One B-rep face of a CAD part: STEP entity #398.
In plain terms, the planar face has unit normal (0, 0, 1).
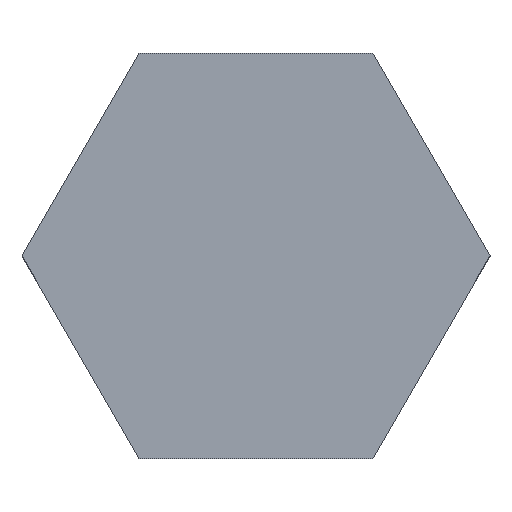
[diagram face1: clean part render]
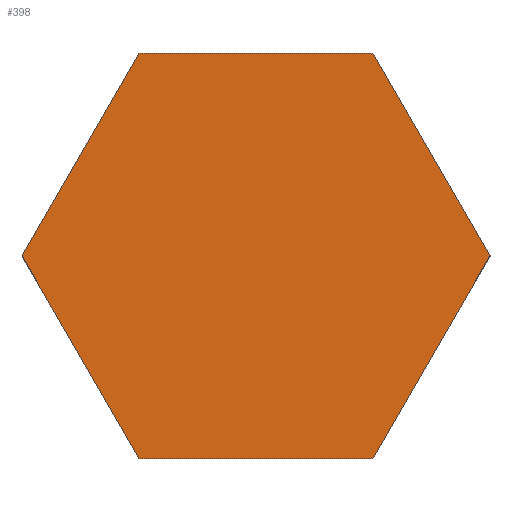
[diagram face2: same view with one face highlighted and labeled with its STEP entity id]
Its self-contained STEP definition (entity closure, numbers rounded to 3 decimals):
#24 = VERTEX_POINT('',#25);
#25 = CARTESIAN_POINT('',(15.,0.,60.));
#32 = PLANE('',#33);
#33 = AXIS2_PLACEMENT_3D('',#34,#35,#36);
#34 = CARTESIAN_POINT('',(15.,0.,54.));
#35 = DIRECTION('',(-0.866,-0.5,0.));
#36 = DIRECTION('',(-0.5,0.866,0.));
#44 = PLANE('',#45);
#45 = AXIS2_PLACEMENT_3D('',#46,#47,#48);
#46 = CARTESIAN_POINT('',(7.5,-12.99,54.));
#47 = DIRECTION('',(-0.866,0.5,0.));
#48 = DIRECTION('',(0.5,0.866,0.));
#56 = EDGE_CURVE('',#24,#57,#59,.T.);
#57 = VERTEX_POINT('',#58);
#58 = CARTESIAN_POINT('',(7.5,12.99,60.));
#59 = SURFACE_CURVE('',#60,(#64,#71),.PCURVE_S1.);
#60 = LINE('',#61,#62);
#61 = CARTESIAN_POINT('',(15.,0.,60.));
#62 = VECTOR('',#63,1.);
#63 = DIRECTION('',(-0.5,0.866,0.));
#64 = PCURVE('',#32,#65);
#65 = DEFINITIONAL_REPRESENTATION('',(#66),#70);
#66 = LINE('',#67,#68);
#67 = CARTESIAN_POINT('',(0.,-6.));
#68 = VECTOR('',#69,1.);
#69 = DIRECTION('',(1.,0.));
#70 = ( GEOMETRIC_REPRESENTATION_CONTEXT(2) 
PARAMETRIC_REPRESENTATION_CONTEXT() REPRESENTATION_CONTEXT('2D SPACE',''
  ) );
#71 = PCURVE('',#72,#77);
#72 = PLANE('',#73);
#73 = AXIS2_PLACEMENT_3D('',#74,#75,#76);
#74 = CARTESIAN_POINT('',(0.,0.,60.));
#75 = DIRECTION('',(0.,0.,1.));
#76 = DIRECTION('',(1.,0.,-0.));
#77 = DEFINITIONAL_REPRESENTATION('',(#78),#82);
#78 = LINE('',#79,#80);
#79 = CARTESIAN_POINT('',(15.,0.));
#80 = VECTOR('',#81,1.);
#81 = DIRECTION('',(-0.5,0.866));
#82 = ( GEOMETRIC_REPRESENTATION_CONTEXT(2) 
PARAMETRIC_REPRESENTATION_CONTEXT() REPRESENTATION_CONTEXT('2D SPACE',''
  ) );
#100 = PLANE('',#101);
#101 = AXIS2_PLACEMENT_3D('',#102,#103,#104);
#102 = CARTESIAN_POINT('',(7.5,12.99,54.));
#103 = DIRECTION('',(0.,-1.,0.));
#104 = DIRECTION('',(-1.,0.,0.));
#144 = VERTEX_POINT('',#145);
#145 = CARTESIAN_POINT('',(7.5,-12.99,60.));
#159 = PLANE('',#160);
#160 = AXIS2_PLACEMENT_3D('',#161,#162,#163);
#161 = CARTESIAN_POINT('',(-7.5,-12.99,54.));
#162 = DIRECTION('',(0.,1.,-0.));
#163 = DIRECTION('',(1.,0.,0.));
#171 = EDGE_CURVE('',#144,#24,#172,.T.);
#172 = SURFACE_CURVE('',#173,(#177,#184),.PCURVE_S1.);
#173 = LINE('',#174,#175);
#174 = CARTESIAN_POINT('',(7.5,-12.99,60.));
#175 = VECTOR('',#176,1.);
#176 = DIRECTION('',(0.5,0.866,0.));
#177 = PCURVE('',#44,#178);
#178 = DEFINITIONAL_REPRESENTATION('',(#179),#183);
#179 = LINE('',#180,#181);
#180 = CARTESIAN_POINT('',(0.,-6.));
#181 = VECTOR('',#182,1.);
#182 = DIRECTION('',(1.,0.));
#183 = ( GEOMETRIC_REPRESENTATION_CONTEXT(2) 
PARAMETRIC_REPRESENTATION_CONTEXT() REPRESENTATION_CONTEXT('2D SPACE',''
  ) );
#184 = PCURVE('',#72,#185);
#185 = DEFINITIONAL_REPRESENTATION('',(#186),#190);
#186 = LINE('',#187,#188);
#187 = CARTESIAN_POINT('',(7.5,-12.99));
#188 = VECTOR('',#189,1.);
#189 = DIRECTION('',(0.5,0.866));
#190 = ( GEOMETRIC_REPRESENTATION_CONTEXT(2) 
PARAMETRIC_REPRESENTATION_CONTEXT() REPRESENTATION_CONTEXT('2D SPACE',''
  ) );
#218 = EDGE_CURVE('',#57,#219,#221,.T.);
#219 = VERTEX_POINT('',#220);
#220 = CARTESIAN_POINT('',(-7.5,12.99,60.));
#221 = SURFACE_CURVE('',#222,(#226,#233),.PCURVE_S1.);
#222 = LINE('',#223,#224);
#223 = CARTESIAN_POINT('',(7.5,12.99,60.));
#224 = VECTOR('',#225,1.);
#225 = DIRECTION('',(-1.,0.,0.));
#226 = PCURVE('',#100,#227);
#227 = DEFINITIONAL_REPRESENTATION('',(#228),#232);
#228 = LINE('',#229,#230);
#229 = CARTESIAN_POINT('',(0.,-6.));
#230 = VECTOR('',#231,1.);
#231 = DIRECTION('',(1.,0.));
#232 = ( GEOMETRIC_REPRESENTATION_CONTEXT(2) 
PARAMETRIC_REPRESENTATION_CONTEXT() REPRESENTATION_CONTEXT('2D SPACE',''
  ) );
#233 = PCURVE('',#72,#234);
#234 = DEFINITIONAL_REPRESENTATION('',(#235),#239);
#235 = LINE('',#236,#237);
#236 = CARTESIAN_POINT('',(7.5,12.99));
#237 = VECTOR('',#238,1.);
#238 = DIRECTION('',(-1.,0.));
#239 = ( GEOMETRIC_REPRESENTATION_CONTEXT(2) 
PARAMETRIC_REPRESENTATION_CONTEXT() REPRESENTATION_CONTEXT('2D SPACE',''
  ) );
#257 = PLANE('',#258);
#258 = AXIS2_PLACEMENT_3D('',#259,#260,#261);
#259 = CARTESIAN_POINT('',(-7.5,12.99,54.));
#260 = DIRECTION('',(0.866,-0.5,0.));
#261 = DIRECTION('',(-0.5,-0.866,0.));
#334 = PLANE('',#335);
#335 = AXIS2_PLACEMENT_3D('',#336,#337,#338);
#336 = CARTESIAN_POINT('',(-15.,0.,54.));
#337 = DIRECTION('',(0.866,0.5,-0.));
#338 = DIRECTION('',(0.5,-0.866,0.));
#398 = ADVANCED_FACE('',(#399),#72,.T.);
#399 = FACE_BOUND('',#400,.T.);
#400 = EDGE_LOOP('',(#401,#402,#403,#426,#449,#470));
#401 = ORIENTED_EDGE('',*,*,#56,.T.);
#402 = ORIENTED_EDGE('',*,*,#218,.T.);
#403 = ORIENTED_EDGE('',*,*,#404,.T.);
#404 = EDGE_CURVE('',#219,#405,#407,.T.);
#405 = VERTEX_POINT('',#406);
#406 = CARTESIAN_POINT('',(-15.,0.,60.));
#407 = SURFACE_CURVE('',#408,(#412,#419),.PCURVE_S1.);
#408 = LINE('',#409,#410);
#409 = CARTESIAN_POINT('',(-7.5,12.99,60.));
#410 = VECTOR('',#411,1.);
#411 = DIRECTION('',(-0.5,-0.866,0.));
#412 = PCURVE('',#72,#413);
#413 = DEFINITIONAL_REPRESENTATION('',(#414),#418);
#414 = LINE('',#415,#416);
#415 = CARTESIAN_POINT('',(-7.5,12.99));
#416 = VECTOR('',#417,1.);
#417 = DIRECTION('',(-0.5,-0.866));
#418 = ( GEOMETRIC_REPRESENTATION_CONTEXT(2) 
PARAMETRIC_REPRESENTATION_CONTEXT() REPRESENTATION_CONTEXT('2D SPACE',''
  ) );
#419 = PCURVE('',#257,#420);
#420 = DEFINITIONAL_REPRESENTATION('',(#421),#425);
#421 = LINE('',#422,#423);
#422 = CARTESIAN_POINT('',(0.,-6.));
#423 = VECTOR('',#424,1.);
#424 = DIRECTION('',(1.,0.));
#425 = ( GEOMETRIC_REPRESENTATION_CONTEXT(2) 
PARAMETRIC_REPRESENTATION_CONTEXT() REPRESENTATION_CONTEXT('2D SPACE',''
  ) );
#426 = ORIENTED_EDGE('',*,*,#427,.T.);
#427 = EDGE_CURVE('',#405,#428,#430,.T.);
#428 = VERTEX_POINT('',#429);
#429 = CARTESIAN_POINT('',(-7.5,-12.99,60.));
#430 = SURFACE_CURVE('',#431,(#435,#442),.PCURVE_S1.);
#431 = LINE('',#432,#433);
#432 = CARTESIAN_POINT('',(-15.,0.,60.));
#433 = VECTOR('',#434,1.);
#434 = DIRECTION('',(0.5,-0.866,0.));
#435 = PCURVE('',#72,#436);
#436 = DEFINITIONAL_REPRESENTATION('',(#437),#441);
#437 = LINE('',#438,#439);
#438 = CARTESIAN_POINT('',(-15.,0.));
#439 = VECTOR('',#440,1.);
#440 = DIRECTION('',(0.5,-0.866));
#441 = ( GEOMETRIC_REPRESENTATION_CONTEXT(2) 
PARAMETRIC_REPRESENTATION_CONTEXT() REPRESENTATION_CONTEXT('2D SPACE',''
  ) );
#442 = PCURVE('',#334,#443);
#443 = DEFINITIONAL_REPRESENTATION('',(#444),#448);
#444 = LINE('',#445,#446);
#445 = CARTESIAN_POINT('',(0.,-6.));
#446 = VECTOR('',#447,1.);
#447 = DIRECTION('',(1.,0.));
#448 = ( GEOMETRIC_REPRESENTATION_CONTEXT(2) 
PARAMETRIC_REPRESENTATION_CONTEXT() REPRESENTATION_CONTEXT('2D SPACE',''
  ) );
#449 = ORIENTED_EDGE('',*,*,#450,.T.);
#450 = EDGE_CURVE('',#428,#144,#451,.T.);
#451 = SURFACE_CURVE('',#452,(#456,#463),.PCURVE_S1.);
#452 = LINE('',#453,#454);
#453 = CARTESIAN_POINT('',(-7.5,-12.99,60.));
#454 = VECTOR('',#455,1.);
#455 = DIRECTION('',(1.,0.,0.));
#456 = PCURVE('',#72,#457);
#457 = DEFINITIONAL_REPRESENTATION('',(#458),#462);
#458 = LINE('',#459,#460);
#459 = CARTESIAN_POINT('',(-7.5,-12.99));
#460 = VECTOR('',#461,1.);
#461 = DIRECTION('',(1.,0.));
#462 = ( GEOMETRIC_REPRESENTATION_CONTEXT(2) 
PARAMETRIC_REPRESENTATION_CONTEXT() REPRESENTATION_CONTEXT('2D SPACE',''
  ) );
#463 = PCURVE('',#159,#464);
#464 = DEFINITIONAL_REPRESENTATION('',(#465),#469);
#465 = LINE('',#466,#467);
#466 = CARTESIAN_POINT('',(0.,-6.));
#467 = VECTOR('',#468,1.);
#468 = DIRECTION('',(1.,0.));
#469 = ( GEOMETRIC_REPRESENTATION_CONTEXT(2) 
PARAMETRIC_REPRESENTATION_CONTEXT() REPRESENTATION_CONTEXT('2D SPACE',''
  ) );
#470 = ORIENTED_EDGE('',*,*,#171,.T.);
